One B-rep face of a CAD part: STEP entity #57930.
In plain terms, the planar face has unit normal (0, 0, 1).
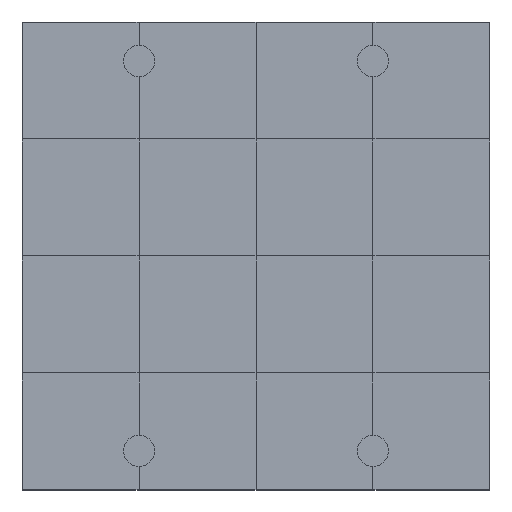
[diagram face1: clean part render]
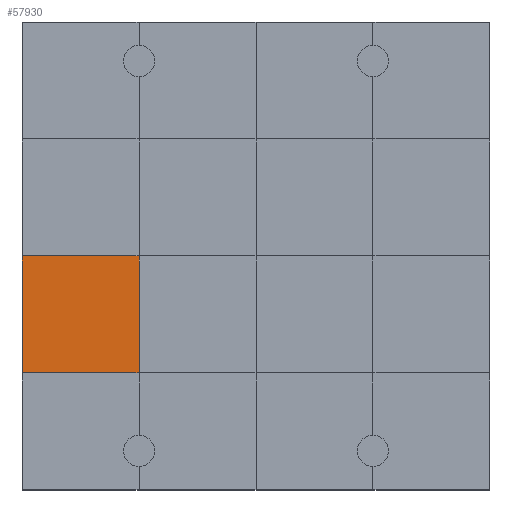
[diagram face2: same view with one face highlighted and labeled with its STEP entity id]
Its self-contained STEP definition (entity closure, numbers rounded to 3 decimals):
#57480 = VERTEX_POINT('',#57481);
#57481 = CARTESIAN_POINT('',(0.,3.,1.2));
#57495 = PLANE('',#57496);
#57496 = AXIS2_PLACEMENT_3D('',#57497,#57498,#57499);
#57497 = CARTESIAN_POINT('',(0.,3.,0.));
#57498 = DIRECTION('',(1.,0.,-0.));
#57499 = DIRECTION('',(0.,0.,1.));
#57521 = PLANE('',#57522);
#57522 = AXIS2_PLACEMENT_3D('',#57523,#57524,#57525);
#57523 = CARTESIAN_POINT('',(0.,0.,1.2));
#57524 = DIRECTION('',(0.,0.,1.));
#57525 = DIRECTION('',(1.,0.,-0.));
#57672 = VERTEX_POINT('',#57673);
#57673 = CARTESIAN_POINT('',(3.,3.,1.2));
#57694 = EDGE_CURVE('',#57480,#57672,#57695,.T.);
#57695 = SURFACE_CURVE('',#57696,(#57700,#57707),.PCURVE_S1.);
#57696 = LINE('',#57697,#57698);
#57697 = CARTESIAN_POINT('',(0.,3.,1.2));
#57698 = VECTOR('',#57699,1.);
#57699 = DIRECTION('',(1.,0.,-0.));
#57700 = PCURVE('',#57521,#57701);
#57701 = DEFINITIONAL_REPRESENTATION('',(#57702),#57706);
#57702 = LINE('',#57703,#57704);
#57703 = CARTESIAN_POINT('',(0.,3.));
#57704 = VECTOR('',#57705,1.);
#57705 = DIRECTION('',(1.,0.));
#57706 = ( GEOMETRIC_REPRESENTATION_CONTEXT(2) 
PARAMETRIC_REPRESENTATION_CONTEXT() REPRESENTATION_CONTEXT('2D SPACE',''
  ) );
#57707 = PCURVE('',#57708,#57713);
#57708 = PLANE('',#57709);
#57709 = AXIS2_PLACEMENT_3D('',#57710,#57711,#57712);
#57710 = CARTESIAN_POINT('',(0.,3.,1.2));
#57711 = DIRECTION('',(0.,0.,1.));
#57712 = DIRECTION('',(1.,0.,-0.));
#57713 = DEFINITIONAL_REPRESENTATION('',(#57714),#57718);
#57714 = LINE('',#57715,#57716);
#57715 = CARTESIAN_POINT('',(0.,0.));
#57716 = VECTOR('',#57717,1.);
#57717 = DIRECTION('',(1.,0.));
#57718 = ( GEOMETRIC_REPRESENTATION_CONTEXT(2) 
PARAMETRIC_REPRESENTATION_CONTEXT() REPRESENTATION_CONTEXT('2D SPACE',''
  ) );
#57753 = VERTEX_POINT('',#57754);
#57754 = CARTESIAN_POINT('',(0.,6.,1.2));
#57780 = EDGE_CURVE('',#57480,#57753,#57781,.T.);
#57781 = SURFACE_CURVE('',#57782,(#57786,#57793),.PCURVE_S1.);
#57782 = LINE('',#57783,#57784);
#57783 = CARTESIAN_POINT('',(0.,3.,1.2));
#57784 = VECTOR('',#57785,1.);
#57785 = DIRECTION('',(-0.,1.,0.));
#57786 = PCURVE('',#57495,#57787);
#57787 = DEFINITIONAL_REPRESENTATION('',(#57788),#57792);
#57788 = LINE('',#57789,#57790);
#57789 = CARTESIAN_POINT('',(1.2,0.));
#57790 = VECTOR('',#57791,1.);
#57791 = DIRECTION('',(0.,-1.));
#57792 = ( GEOMETRIC_REPRESENTATION_CONTEXT(2) 
PARAMETRIC_REPRESENTATION_CONTEXT() REPRESENTATION_CONTEXT('2D SPACE',''
  ) );
#57793 = PCURVE('',#57708,#57794);
#57794 = DEFINITIONAL_REPRESENTATION('',(#57795),#57799);
#57795 = LINE('',#57796,#57797);
#57796 = CARTESIAN_POINT('',(0.,0.));
#57797 = VECTOR('',#57798,1.);
#57798 = DIRECTION('',(0.,1.));
#57799 = ( GEOMETRIC_REPRESENTATION_CONTEXT(2) 
PARAMETRIC_REPRESENTATION_CONTEXT() REPRESENTATION_CONTEXT('2D SPACE',''
  ) );
#57930 = ADVANCED_FACE('',(#57931),#57708,.T.);
#57931 = FACE_BOUND('',#57932,.T.);
#57932 = EDGE_LOOP('',(#57933,#57934,#57935,#57963));
#57933 = ORIENTED_EDGE('',*,*,#57780,.F.);
#57934 = ORIENTED_EDGE('',*,*,#57694,.T.);
#57935 = ORIENTED_EDGE('',*,*,#57936,.T.);
#57936 = EDGE_CURVE('',#57672,#57937,#57939,.T.);
#57937 = VERTEX_POINT('',#57938);
#57938 = CARTESIAN_POINT('',(3.,6.,1.2));
#57939 = SURFACE_CURVE('',#57940,(#57944,#57951),.PCURVE_S1.);
#57940 = LINE('',#57941,#57942);
#57941 = CARTESIAN_POINT('',(3.,3.,1.2));
#57942 = VECTOR('',#57943,1.);
#57943 = DIRECTION('',(-0.,1.,0.));
#57944 = PCURVE('',#57708,#57945);
#57945 = DEFINITIONAL_REPRESENTATION('',(#57946),#57950);
#57946 = LINE('',#57947,#57948);
#57947 = CARTESIAN_POINT('',(3.,0.));
#57948 = VECTOR('',#57949,1.);
#57949 = DIRECTION('',(0.,1.));
#57950 = ( GEOMETRIC_REPRESENTATION_CONTEXT(2) 
PARAMETRIC_REPRESENTATION_CONTEXT() REPRESENTATION_CONTEXT('2D SPACE',''
  ) );
#57951 = PCURVE('',#57952,#57957);
#57952 = PLANE('',#57953);
#57953 = AXIS2_PLACEMENT_3D('',#57954,#57955,#57956);
#57954 = CARTESIAN_POINT('',(3.,3.,1.2));
#57955 = DIRECTION('',(0.,0.,1.));
#57956 = DIRECTION('',(1.,0.,-0.));
#57957 = DEFINITIONAL_REPRESENTATION('',(#57958),#57962);
#57958 = LINE('',#57959,#57960);
#57959 = CARTESIAN_POINT('',(0.,0.));
#57960 = VECTOR('',#57961,1.);
#57961 = DIRECTION('',(0.,1.));
#57962 = ( GEOMETRIC_REPRESENTATION_CONTEXT(2) 
PARAMETRIC_REPRESENTATION_CONTEXT() REPRESENTATION_CONTEXT('2D SPACE',''
  ) );
#57963 = ORIENTED_EDGE('',*,*,#57964,.F.);
#57964 = EDGE_CURVE('',#57753,#57937,#57965,.T.);
#57965 = SURFACE_CURVE('',#57966,(#57970,#57977),.PCURVE_S1.);
#57966 = LINE('',#57967,#57968);
#57967 = CARTESIAN_POINT('',(0.,6.,1.2));
#57968 = VECTOR('',#57969,1.);
#57969 = DIRECTION('',(1.,0.,-0.));
#57970 = PCURVE('',#57708,#57971);
#57971 = DEFINITIONAL_REPRESENTATION('',(#57972),#57976);
#57972 = LINE('',#57973,#57974);
#57973 = CARTESIAN_POINT('',(0.,3.));
#57974 = VECTOR('',#57975,1.);
#57975 = DIRECTION('',(1.,0.));
#57976 = ( GEOMETRIC_REPRESENTATION_CONTEXT(2) 
PARAMETRIC_REPRESENTATION_CONTEXT() REPRESENTATION_CONTEXT('2D SPACE',''
  ) );
#57977 = PCURVE('',#57978,#57983);
#57978 = PLANE('',#57979);
#57979 = AXIS2_PLACEMENT_3D('',#57980,#57981,#57982);
#57980 = CARTESIAN_POINT('',(0.,6.,1.2));
#57981 = DIRECTION('',(0.,0.,1.));
#57982 = DIRECTION('',(1.,0.,-0.));
#57983 = DEFINITIONAL_REPRESENTATION('',(#57984),#57988);
#57984 = LINE('',#57985,#57986);
#57985 = CARTESIAN_POINT('',(0.,0.));
#57986 = VECTOR('',#57987,1.);
#57987 = DIRECTION('',(1.,0.));
#57988 = ( GEOMETRIC_REPRESENTATION_CONTEXT(2) 
PARAMETRIC_REPRESENTATION_CONTEXT() REPRESENTATION_CONTEXT('2D SPACE',''
  ) );
